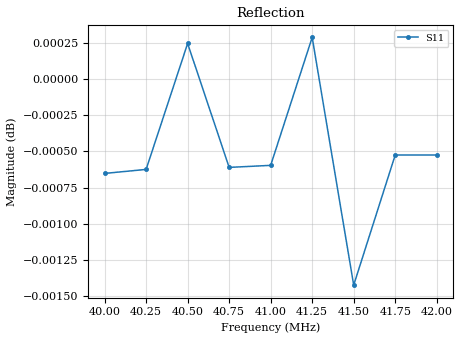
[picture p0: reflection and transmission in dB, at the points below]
# Hz S RI R 50
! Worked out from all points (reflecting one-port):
!   9 points, 40 MHz to 42 MHz, reference 50 ohm
!   lowest |S11| = 0.0 dB at 41.5 MHz (marker M1)
!   phase of S11 starts at -1 deg and turns -0 deg over the sweep
4e7  0.9998 -0.0158
4.025e7  0.9998 -0.016
4.05e7  0.9999 -0.016
4.075e7  0.9998 -0.0161
4.1e7  0.9998 -0.0162
4.125e7  0.9999 -0.0163
4.15e7  0.9997 -0.0165
4.175e7  0.9998 -0.0167
4.2e7  0.9998 -0.0167
